VERSION 5.7 ;
  NOWIREEXTENSIONATPIN ON ;
  DIVIDERCHAR "/" ;
  BUSBITCHARS "[]" ;
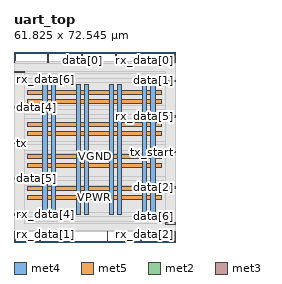
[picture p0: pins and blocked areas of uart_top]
MACRO uart_top
  CLASS BLOCK ;
  FOREIGN uart_top ;
  ORIGIN 0.000 0.000 ;
  SIZE 61.825 BY 72.545 ;
  PIN VGND
    DIRECTION INOUT ;
    USE GROUND ;
    PORT
      LAYER met4 ;
        RECT 14.340 10.640 15.940 60.080 ;
    END
    PORT
      LAYER met4 ;
        RECT 26.985 10.640 28.585 60.080 ;
    END
    PORT
      LAYER met4 ;
        RECT 39.630 10.640 41.230 60.080 ;
    END
    PORT
      LAYER met4 ;
        RECT 52.275 10.640 53.875 60.080 ;
    END
    PORT
      LAYER met5 ;
        RECT 5.280 19.500 56.360 21.100 ;
    END
    PORT
      LAYER met5 ;
        RECT 5.280 31.740 56.360 33.340 ;
    END
    PORT
      LAYER met5 ;
        RECT 5.280 43.980 56.360 45.580 ;
    END
    PORT
      LAYER met5 ;
        RECT 5.280 56.220 56.360 57.820 ;
    END
  END VGND
  PIN VPWR
    DIRECTION INOUT ;
    USE POWER ;
    PORT
      LAYER met4 ;
        RECT 11.040 10.640 12.640 60.080 ;
    END
    PORT
      LAYER met4 ;
        RECT 23.685 10.640 25.285 60.080 ;
    END
    PORT
      LAYER met4 ;
        RECT 36.330 10.640 37.930 60.080 ;
    END
    PORT
      LAYER met4 ;
        RECT 48.975 10.640 50.575 60.080 ;
    END
    PORT
      LAYER met5 ;
        RECT 5.280 16.200 56.360 17.800 ;
    END
    PORT
      LAYER met5 ;
        RECT 5.280 28.440 56.360 30.040 ;
    END
    PORT
      LAYER met5 ;
        RECT 5.280 40.680 56.360 42.280 ;
    END
    PORT
      LAYER met5 ;
        RECT 5.280 52.920 56.360 54.520 ;
    END
  END VPWR
  PIN clk
    DIRECTION INPUT ;
    USE SIGNAL ;
    ANTENNAGATEAREA 0.852000 ;
    PORT
      LAYER met2 ;
        RECT 51.610 68.545 51.890 72.545 ;
    END
  END clk
  PIN data[0]
    DIRECTION INPUT ;
    USE SIGNAL ;
    ANTENNAGATEAREA 0.196500 ;
    PORT
      LAYER met2 ;
        RECT 25.850 68.545 26.130 72.545 ;
    END
  END data[0]
  PIN data[1]
    DIRECTION INPUT ;
    USE SIGNAL ;
    ANTENNAGATEAREA 0.196500 ;
    PORT
      LAYER met3 ;
        RECT 57.825 61.240 61.825 61.840 ;
    END
  END data[1]
  PIN data[2]
    DIRECTION INPUT ;
    USE SIGNAL ;
    ANTENNAGATEAREA 0.196500 ;
    PORT
      LAYER met3 ;
        RECT 57.825 20.440 61.825 21.040 ;
    END
  END data[2]
  PIN data[3]
    DIRECTION INPUT ;
    USE SIGNAL ;
    ANTENNAGATEAREA 0.196500 ;
    PORT
      LAYER met2 ;
        RECT 12.970 68.545 13.250 72.545 ;
    END
  END data[3]
  PIN data[4]
    DIRECTION INPUT ;
    USE SIGNAL ;
    ANTENNAGATEAREA 0.196500 ;
    PORT
      LAYER met3 ;
        RECT 0.000 51.040 4.000 51.640 ;
    END
  END data[4]
  PIN data[5]
    DIRECTION INPUT ;
    USE SIGNAL ;
    ANTENNAGATEAREA 0.196500 ;
    PORT
      LAYER met3 ;
        RECT 0.000 23.840 4.000 24.440 ;
    END
  END data[5]
  PIN data[6]
    DIRECTION INPUT ;
    USE SIGNAL ;
    ANTENNAGATEAREA 0.196500 ;
    PORT
      LAYER met3 ;
        RECT 57.825 6.840 61.825 7.440 ;
    END
  END data[6]
  PIN data[7]
    DIRECTION INPUT ;
    USE SIGNAL ;
    ANTENNAGATEAREA 0.196500 ;
    PORT
      LAYER met2 ;
        RECT 48.390 0.000 48.670 4.000 ;
    END
  END data[7]
  PIN rst
    DIRECTION INPUT ;
    USE SIGNAL ;
    ANTENNAGATEAREA 0.196500 ;
    PORT
      LAYER met2 ;
        RECT 0.090 0.000 0.370 4.000 ;
    END
  END rst
  PIN rx_data[0]
    DIRECTION OUTPUT TRISTATE ;
    USE SIGNAL ;
    ANTENNADIFFAREA 0.795200 ;
    PORT
      LAYER met2 ;
        RECT 61.270 68.545 61.550 72.545 ;
    END
  END rx_data[0]
  PIN rx_data[1]
    DIRECTION OUTPUT TRISTATE ;
    USE SIGNAL ;
    ANTENNADIFFAREA 0.795200 ;
    PORT
      LAYER met2 ;
        RECT 9.750 0.000 10.030 4.000 ;
    END
  END rx_data[1]
  PIN rx_data[2]
    DIRECTION OUTPUT TRISTATE ;
    USE SIGNAL ;
    ANTENNADIFFAREA 0.795200 ;
    PORT
      LAYER met2 ;
        RECT 61.270 0.000 61.550 4.000 ;
    END
  END rx_data[2]
  PIN rx_data[3]
    DIRECTION OUTPUT TRISTATE ;
    USE SIGNAL ;
    ANTENNADIFFAREA 0.795200 ;
    PORT
      LAYER met2 ;
        RECT 22.630 0.000 22.910 4.000 ;
    END
  END rx_data[3]
  PIN rx_data[4]
    DIRECTION OUTPUT TRISTATE ;
    USE SIGNAL ;
    ANTENNADIFFAREA 0.795200 ;
    PORT
      LAYER met3 ;
        RECT 0.000 10.240 4.000 10.840 ;
    END
  END rx_data[4]
  PIN rx_data[5]
    DIRECTION OUTPUT TRISTATE ;
    USE SIGNAL ;
    ANTENNADIFFAREA 0.795200 ;
    PORT
      LAYER met3 ;
        RECT 57.825 47.640 61.825 48.240 ;
    END
  END rx_data[5]
  PIN rx_data[6]
    DIRECTION OUTPUT TRISTATE ;
    USE SIGNAL ;
    ANTENNADIFFAREA 0.795200 ;
    PORT
      LAYER met3 ;
        RECT 0.000 64.640 4.000 65.240 ;
    END
  END rx_data[6]
  PIN rx_data[7]
    DIRECTION OUTPUT TRISTATE ;
    USE SIGNAL ;
    ANTENNADIFFAREA 0.795200 ;
    PORT
      LAYER met2 ;
        RECT 38.730 68.545 39.010 72.545 ;
    END
  END rx_data[7]
  PIN rx_done
    DIRECTION OUTPUT TRISTATE ;
    USE SIGNAL ;
    ANTENNADIFFAREA 0.795200 ;
    PORT
      LAYER met2 ;
        RECT 35.510 0.000 35.790 4.000 ;
    END
  END rx_done
  PIN tx
    DIRECTION OUTPUT TRISTATE ;
    USE SIGNAL ;
    ANTENNADIFFAREA 0.795200 ;
    PORT
      LAYER met3 ;
        RECT 0.000 37.440 4.000 38.040 ;
    END
  END tx
  PIN tx_done
    DIRECTION OUTPUT TRISTATE ;
    USE SIGNAL ;
    ANTENNADIFFAREA 0.795200 ;
    PORT
      LAYER met2 ;
        RECT 0.090 68.545 0.370 72.545 ;
    END
  END tx_done
  PIN tx_start
    DIRECTION INPUT ;
    USE SIGNAL ;
    ANTENNAGATEAREA 0.196500 ;
    PORT
      LAYER met3 ;
        RECT 57.825 34.040 61.825 34.640 ;
    END
  END tx_start
  OBS
      LAYER li1 ;
        RECT 5.520 10.795 56.120 59.925 ;
      LAYER met1 ;
        RECT 0.070 10.640 61.570 60.080 ;
      LAYER met2 ;
        RECT 0.650 68.265 12.690 69.090 ;
        RECT 13.530 68.265 25.570 69.090 ;
        RECT 26.410 68.265 38.450 69.090 ;
        RECT 39.290 68.265 51.330 69.090 ;
        RECT 52.170 68.265 60.990 69.090 ;
        RECT 0.100 4.280 61.540 68.265 ;
        RECT 0.650 4.000 9.470 4.280 ;
        RECT 10.310 4.000 22.350 4.280 ;
        RECT 23.190 4.000 35.230 4.280 ;
        RECT 36.070 4.000 48.110 4.280 ;
        RECT 48.950 4.000 60.990 4.280 ;
      LAYER met3 ;
        RECT 4.400 64.240 57.825 65.105 ;
        RECT 4.000 62.240 57.825 64.240 ;
        RECT 4.000 60.840 57.425 62.240 ;
        RECT 4.000 52.040 57.825 60.840 ;
        RECT 4.400 50.640 57.825 52.040 ;
        RECT 4.000 48.640 57.825 50.640 ;
        RECT 4.000 47.240 57.425 48.640 ;
        RECT 4.000 38.440 57.825 47.240 ;
        RECT 4.400 37.040 57.825 38.440 ;
        RECT 4.000 35.040 57.825 37.040 ;
        RECT 4.000 33.640 57.425 35.040 ;
        RECT 4.000 24.840 57.825 33.640 ;
        RECT 4.400 23.440 57.825 24.840 ;
        RECT 4.000 21.440 57.825 23.440 ;
        RECT 4.000 20.040 57.425 21.440 ;
        RECT 4.000 11.240 57.825 20.040 ;
        RECT 4.400 9.840 57.825 11.240 ;
        RECT 4.000 7.840 57.825 9.840 ;
        RECT 4.000 6.975 57.425 7.840 ;
  END
END uart_top
END LIBRARY

